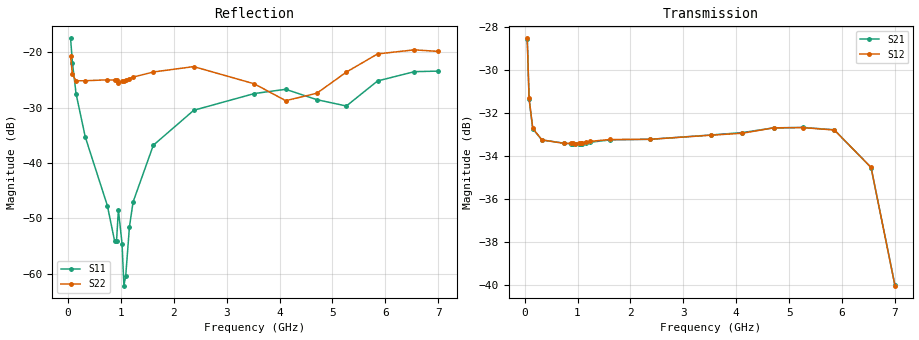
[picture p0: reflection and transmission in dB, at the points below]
! Integrated Device Technology
! Corporate Headquarters
! 6024 Silver Creek Valley Road
! San Jose, CA 95138  USA
! Phone:  1-408-284-8200
! Toll Free:  1-800-223-1366
! Webpage:  http://www.idt.com/
! Timing and RF Division
! 515 Groton Road, Suite 102
! Westford, MA 01886-6024
! Device:  F2258
! Description: Voltage Variable RF Attenuator
! Frequency:  50.0 -  6000.00 MHz
! Package:  3x3 mm Thin QFN Plastic Package: 16 pin
! Ports:  2 RF, 2 DC
!  Pin  1  = NC
!  Pin  2  = NC
!  Pin  3  = RF2  = Port 2
!  Pin  4  = GND
!  Pin  5  = Vdd
!  Pin  6  = NC
!  Pin  7  = VCTRL
!  Pin  8  = NC
!  Pin  9  = GND
!  Pin 10  = RF1  = Port 1
!  Pin 11  = NC
!  Pin 12  = NC
!  Pin 13  = NC
!  Pin 14  = NC
!  Pin 15  = NC
!  Pin 16  = NC
! Vcntrl:  1.800 Volts
! Vdd:  +3.300 Volts
! Current:  1.157 mA
! Data:  The device was measured on a the F2258 evaluation board which has
!  individual transmission lines to the RF pins.  Data was collected
!  using a calibrated network analyzer.  The evaluation board was
!  de-embedded using a TRL calibration technique.
!  The reference plane is the edge of the package pin.
! Misc:  SN 10
!  Action Tracker AT0285
! Date Measured:  2014-12-10
! Date:  2016-01-13  MJV
! Note:
!  Integrated Device Technology supplies this data as a sample of measured
!  data at the package pin for this product.  Your particular data for this
!  product may vary.
!  Data was taken at 25 degrees C.
!  Integrated Device Technology reserves the right to change this data at anytime.
!Freq_(GHz)  S11M_(dB)  S11P_(deg)  S21M_(dB)  S21P_(deg)  S12M_(dB)  S12P_(deg)  S22M_(dB)  S22P_(deg)
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# GHz S dB R 50
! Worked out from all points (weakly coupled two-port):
!   201 points, 50 MHz to 7 GHz, reference 50 ohm
!   highest |S21| = -28.57 dB at 50 MHz (marker M1); lowest = -40.0 dB at 7 GHz (marker M2)
!   lowest |S11| = -62.1 dB at 1.058 GHz (marker M3), VSWR 1.00, Z = 49.9 + j0.0391 ohm
!   |S11| at or under -10 dB: start of sweep to end of sweep
!   |S22| runs from -29.0 to -19.3 dB; largest |S21 - S12| = 0.00012
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0.05  -17.54 -110.6  -28.57 -60.4  -28.55 -60.3  -20.72 -89.7
0.08475  -21.97 -106.9  -31.35 -42.2  -31.33 -42.1  -24.05 -58.3
0.15425  -27.55 -107.2  -32.75 -25.7  -32.72 -25.6  -25.19 -31.9
0.328  -35.32 -113.3  -33.26 -14.0  -33.26 -14.0  -25.18 -13.9
0.745  -47.68 -137.8  -33.41 -9.7  -33.42 -9.7  -25.01 -6.4
0.884  -54.14 166.5  -33.44 -9.5  -33.42 -9.5  -25.06 -6.8
0.91875  -54.03 146.3  -33.43 -9.5  -33.41 -9.5  -25.06 -7.0
0.9535  -48.46 -157.9  -33.45 -9.5  -33.43 -9.5  -25.53 -5.0
1.023  -54.53 177.1  -33.43 -9.5  -33.41 -9.5  -25.28 -6.0
1.05775  -62.11 150.1  -33.43 -9.6  -33.40 -9.6  -25.16 -5.7
1.0925  -60.34 96.9  -33.43 -9.6  -33.39 -9.6  -25.07 -5.8
1.162  -51.56 58.9  -33.40 -9.7  -33.36 -9.7  -24.78 -6.0
1.2315  -47.02 40.7  -33.37 -10.0  -33.33 -10.0  -24.52 -6.3
1.61375  -36.80 30.9  -33.26 -12.2  -33.24 -12.2  -23.60 -7.6
2.37825  -30.50 47.1  -33.23 -16.9  -33.23 -16.9  -22.63 -8.2
3.525  -27.48 91.2  -33.03 -24.8  -33.04 -24.7  -25.74 -6.6
4.11575  -26.72 104.7  -32.92 -29.3  -32.95 -29.2  -28.77 -12.6
4.7065  -28.59 95.3  -32.70 -34.7  -32.70 -34.8  -27.42 -27.0
5.2625  -29.73 53.6  -32.68 -40.9  -32.69 -40.9  -23.62 -34.9
5.85325  -25.21 29.4  -32.79 -50.7  -32.80 -50.6  -20.34 -37.4
6.54825  -23.54 44.7  -34.54 -68.4  -34.53 -68.4  -19.61 -64.0
7  -23.44 84.2  -39.99 -65.9  -40.02 -65.6  -19.89 -123.3
